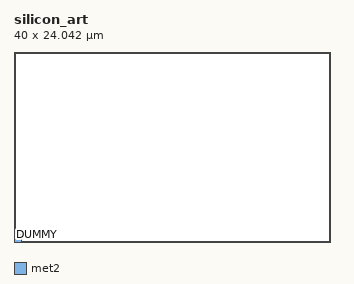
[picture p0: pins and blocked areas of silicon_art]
MACRO silicon_art
  CLASS COVER ;
  SIZE 40.000 BY 24.042 ;
  ORIGIN 0.000 0.000 ;
  PIN DUMMY
    DIRECTION OUTPUT ;
    PORT
      LAYER met2 ;
        RECT 0.000 0.000 1.000 1.000 ;
    END
  END DUMMY
END silicon_art
